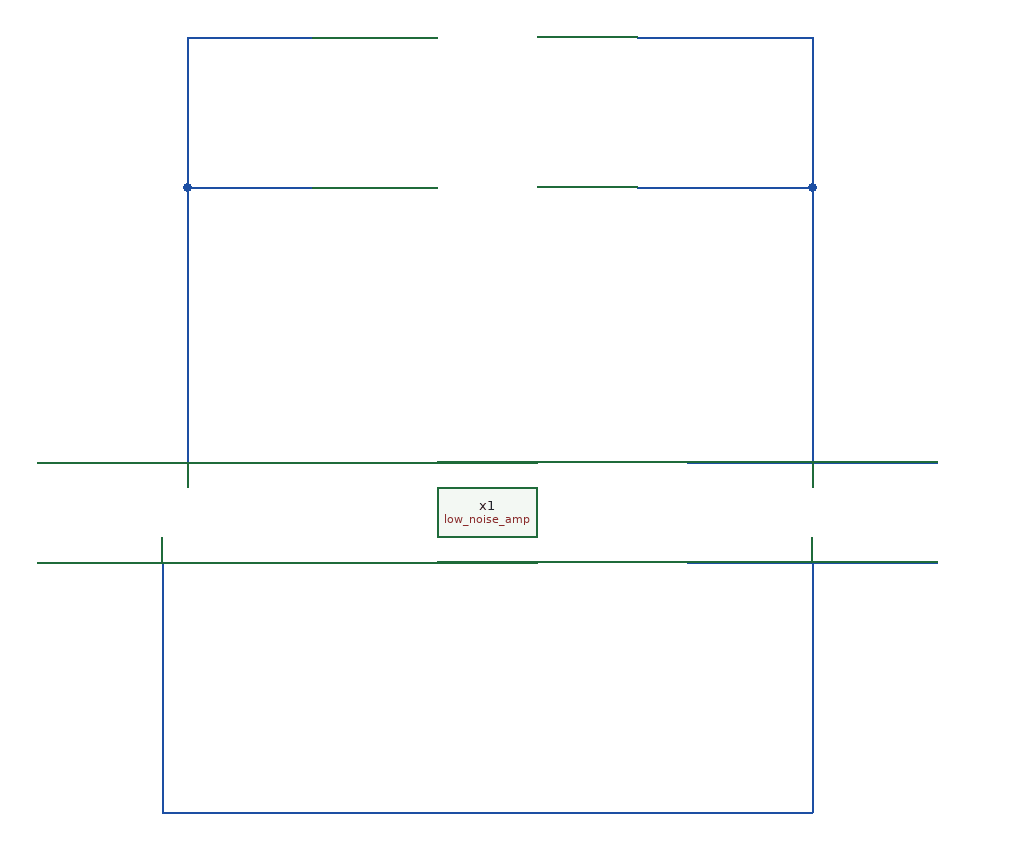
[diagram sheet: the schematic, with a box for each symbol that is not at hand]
v {xschem version=3.4.5 file_version=1.2
}
G {}
K {}
V {}
S {}
E {}
N 640 -420 840 -420 {}
N 120 -420 320 -420 {}
N 740 -640 740 -420 {}
N 600 -640 740 -640 {}
N 240 -640 340 -640 {}
N 240 -640 240 -420 {}
N 120 -340 320 -340 {}
N 640 -340 840 -340 {}
N 740 -340 740 -140 {}
N 220 -140 740 -140 {}
N 220 -340 220 -140 {}
N 240 -760 240 -640 {}
N 240 -760 340 -760 {}
N 600 -760 740 -760 {}
N 740 -760 740 -640 {}
C {low_noise_amp.sym} 480 -380 0 0 {name=x1}
